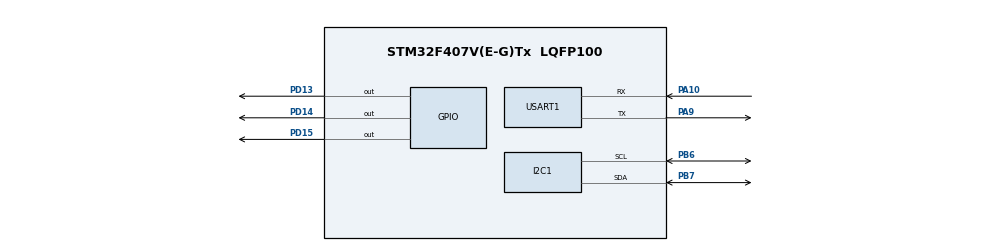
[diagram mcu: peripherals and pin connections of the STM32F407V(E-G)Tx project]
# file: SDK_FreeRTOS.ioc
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FREERTOS.Queues01=myQueue01,16,uint16_t,0,Dynamic,NULL,NULL
FREERTOS.Tasks01=Task_LED1,0,128,StartTaskLED1,Default,NULL,Dynamic,NULL,NULL;Task_UART,0,128,StartTaskUART,Default,NULL,Dynamic,NULL,NULL;Task_LED2,0,128,StartTasLED2,Default,NULL,Dynamic,NULL,NULL
FREERTOS.configENABLE_BACKWARD_COMPATIBILITY=0
FREERTOS.configGENERATE_RUN_TIME_STATS=1
FREERTOS.configUSE_STATS_FORMATTING_FUNCTIONS=1
FREERTOS.configUSE_TRACE_FACILITY=1
Mcu.Family=STM32F4
Mcu.Name=STM32F407V(E-G)Tx
Mcu.Package=LQFP100
NVIC.PriorityGroup=NVIC_PRIORITYGROUP_4
NVIC.TIM1_UP_TIM10_IRQn=true\:0\:0\:false\:false\:true\:false\:false\:true\:true
NVIC.TimeBase=TIM1_UP_TIM10_IRQn
NVIC.TimeBaseIP=TIM1
PA10.Mode=Asynchronous
PA10.Signal=USART1_RX
PA13.Mode=JTAG_5_pins
PA13.Signal=SYS_JTMS-SWDIO
PA14.Mode=JTAG_5_pins
PA14.Signal=SYS_JTCK-SWCLK
PA15.Mode=JTAG_5_pins
PA15.Signal=SYS_JTDI
PA9.Mode=Asynchronous
PA9.Signal=USART1_TX
PB3.Mode=JTAG_5_pins
PB3.Signal=SYS_JTDO-SWO
PB4.Mode=JTAG_5_pins
PB4.Signal=SYS_JTRST
PB6.Mode=I2C
PB6.Signal=I2C1_SCL
PB7.Mode=I2C
PB7.Signal=I2C1_SDA
PD13.Signal=GPIO_Output
PD14.Signal=GPIO_Output
PD15.Signal=GPIO_Output
PH0-OSC_IN.Mode=HSE-External-Oscillator
PH0-OSC_IN.Signal=RCC_OSC_IN
PH1-OSC_OUT.Mode=HSE-External-Oscillator
PH1-OSC_OUT.Signal=RCC_OSC_OUT
ProjectManager.HeapSize=0x200
ProjectManager.StackSize=0x400
ProjectManager.TargetToolchain=STM32CubeIDE
RCC.AHBFreq_Value=16000000
RCC.APB1Freq_Value=16000000
RCC.APB2Freq_Value=16000000
RCC.CortexFreq_Value=16000000
RCC.HSE_VALUE=25000000
RCC.HSI_VALUE=16000000
RCC.LSE_VALUE=32768
RCC.SYSCLKFreq_VALUE=16000000
RCC.VCOOutputFreq_Value=192000000
USART1.VirtualMode=VM_ASYNC
VP_FREERTOS_VS_CMSIS_V1.Mode=CMSIS_V1
VP_SYS_VS_tim1.Mode=TIM1
board=custom

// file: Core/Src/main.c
/**
  ******************************************************************************
  * @file           : main.c
  * @brief          : Main program body
  ******************************************************************************
  * This notice applies to any and all portions of this file
  * that are not between comment pairs USER CODE BEGIN and
  * USER CODE END. Other portions of this file, whether
  * inserted by the user or by software development tools
  * are owned by their respective copyright owners.
  *
  * Copyright (c) 2019 STMicroelectronics International N.V.
  * All rights reserved.
  *
  * Redistribution and use in source and binary forms, with or without
  * modification, are permitted, provided that the following conditions are met:
  *
  * 1. Redistribution of source code must retain the above copyright notice,
  *    this list of conditions and the following disclaimer.
  * 2. Redistributions in binary form must reproduce the above copyright notice,
  *    this list of conditions and the following disclaimer in the documentation
  *    and/or other materials provided with the distribution.
  * 3. Neither the name of STMicroelectronics nor the names of other
  *    contributors to this software may be used to endorse or promote products
  *    derived from this software without specific written permission.
  * 4. This software, including modifications and/or derivative works of this
  *    software, must execute solely and exclusively on microcontroller or
  *    microprocessor devices manufactured by or for STMicroelectronics.
  * 5. Redistribution and use of this software other than as permitted under
  *    this license is void and will automatically terminate your rights under
  *    this license.
  *
  * THIS SOFTWARE IS PROVIDED BY STMICROELECTRONICS AND CONTRIBUTORS "AS IS"
  * AND ANY EXPRESS, IMPLIED OR STATUTORY WARRANTIES, INCLUDING, BUT NOT
  * LIMITED TO, THE IMPLIED WARRANTIES OF MERCHANTABILITY, FITNESS FOR A
  * PARTICULAR PURPOSE AND NON-INFRINGEMENT OF THIRD PARTY INTELLECTUAL PROPERTY
  * RIGHTS ARE DISCLAIMED TO THE FULLEST EXTENT PERMITTED BY LAW. IN NO EVENT
  * SHALL STMICROELECTRONICS OR CONTRIBUTORS BE LIABLE FOR ANY DIRECT, INDIRECT,
  * INCIDENTAL, SPECIAL, EXEMPLARY, OR CONSEQUENTIAL DAMAGES (INCLUDING, BUT NOT
  * LIMITED TO, PROCUREMENT OF SUBSTITUTE GOODS OR SERVICES; LOSS OF USE, DATA,
  * OR PROFITS; OR BUSINESS INTERRUPTION) HOWEVER CAUSED AND ON ANY THEORY OF
  * LIABILITY, WHETHER IN CONTRACT, STRICT LIABILITY, OR TORT (INCLUDING
  * NEGLIGENCE OR OTHERWISE) ARISING IN ANY WAY OUT OF THE USE OF THIS SOFTWARE,
  * EVEN IF ADVISED OF THE POSSIBILITY OF SUCH DAMAGE.
  *
  ******************************************************************************
  */
/* USER CODE END Header */

#include "main.h"
#include "cmsis_os.h"
#include "usart.h"
#include "gpio.h"
#include "oled.h"

void SystemClock_Config(void);
void MX_FREERTOS_Init(void);
/* USER CODE BEGIN PFP */
void MX_I2C1_Init(void);
/* USER CODE END PFP */

int main(void)
{

  /* MCU Configuration--------------------------------------------------------*/

  /* Reset of all peripherals, Initializes the Flash interface and the Systick. */
  HAL_Init();

  /* Configure the system clock */
  SystemClock_Config();

  /* Initialize all configured peripherals */
  MX_GPIO_Init();
  MX_USART1_UART_Init();
  /* USER CODE BEGIN 2 */
  MX_I2C1_Init();
  oled_Init();
  /* USER CODE END 2 */

  /* Call init function for freertos objects (in freertos.c) */
  MX_FREERTOS_Init();
  /* Start scheduler */
  osKernelStart();

  /* We should never get here as control is now taken by the scheduler */
  /* Infinite loop */
  while (1)
  {

  }
}

void SystemClock_Config(void)
{
  RCC_OscInitTypeDef RCC_OscInitStruct = {0};
  RCC_ClkInitTypeDef RCC_ClkInitStruct = {0};

  __HAL_RCC_PWR_CLK_ENABLE();
  __HAL_PWR_VOLTAGESCALING_CONFIG(PWR_REGULATOR_VOLTAGE_SCALE1);

  RCC_OscInitStruct.OscillatorType = RCC_OSCILLATORTYPE_HSE;
  RCC_OscInitStruct.HSEState = RCC_HSE_ON;
  RCC_OscInitStruct.PLL.PLLState = RCC_PLL_ON;
  RCC_OscInitStruct.PLL.PLLSource = RCC_PLLSOURCE_HSE;
  RCC_OscInitStruct.PLL.PLLM = 25;
  RCC_OscInitStruct.PLL.PLLN = 336;
  RCC_OscInitStruct.PLL.PLLP = RCC_PLLP_DIV2;
  RCC_OscInitStruct.PLL.PLLQ = 4;
  if (HAL_RCC_OscConfig(&RCC_OscInitStruct) != HAL_OK)
  {
    Error_Handler();
  }

  RCC_ClkInitStruct.ClockType = RCC_CLOCKTYPE_HCLK|RCC_CLOCKTYPE_SYSCLK
                              |RCC_CLOCKTYPE_PCLK1|RCC_CLOCKTYPE_PCLK2;
  RCC_ClkInitStruct.SYSCLKSource = RCC_SYSCLKSOURCE_PLLCLK;
  RCC_ClkInitStruct.AHBCLKDivider = RCC_SYSCLK_DIV1;
  RCC_ClkInitStruct.APB1CLKDivider = RCC_HCLK_DIV4;
  RCC_ClkInitStruct.APB2CLKDivider = RCC_HCLK_DIV2;

  if (HAL_RCC_ClockConfig(&RCC_ClkInitStruct, FLASH_LATENCY_5) != HAL_OK)
  {
    Error_Handler();
  }
}

 /**
  * @brief  Period elapsed callback in non blocking mode
  * @note   This function is called  when TIM1 interrupt took place, inside
  * HAL_TIM_IRQHandler(). It makes a direct call to HAL_IncTick() to increment
  * a global variable "uwTick" used as application time base.
  * @param  htim : TIM handle
  * @retval None
  */
void HAL_TIM_PeriodElapsedCallback(TIM_HandleTypeDef *htim)
{
  if (htim->Instance == TIM1) {
    HAL_IncTick();
  }
}

void Error_Handler(void)
{
}

/************************ (C) COPYRIGHT STMicroelectronics *****END OF FILE****/

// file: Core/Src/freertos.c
/* USER CODE BEGIN Header */
/**
  ******************************************************************************
  * File Name          : freertos.c
  * Description        : Code for freertos applications
  ******************************************************************************
  * This notice applies to any and all portions of this file
  * that are not between comment pairs USER CODE BEGIN and
  * USER CODE END. Other portions of this file, whether
  * inserted by the user or by software development tools
  * are owned by their respective copyright owners.
  *
  * Copyright (c) 2019 STMicroelectronics International N.V.
  * All rights reserved.
  *
  * Redistribution and use in source and binary forms, with or without
  * modification, are permitted, provided that the following conditions are met:
  *
  * 1. Redistribution of source code must retain the above copyright notice,
  *    this list of conditions and the following disclaimer.
  * 2. Redistributions in binary form must reproduce the above copyright notice,
  *    this list of conditions and the following disclaimer in the documentation
  *    and/or other materials provided with the distribution.
  * 3. Neither the name of STMicroelectronics nor the names of other
  *    contributors to this software may be used to endorse or promote products
  *    derived from this software without specific written permission.
  * 4. This software, including modifications and/or derivative works of this
  *    software, must execute solely and exclusively on microcontroller or
  *    microprocessor devices manufactured by or for STMicroelectronics.
  * 5. Redistribution and use of this software other than as permitted under
  *    this license is void and will automatically terminate your rights under
  *    this license.
  *
  * THIS SOFTWARE IS PROVIDED BY STMICROELECTRONICS AND CONTRIBUTORS "AS IS"
  * AND ANY EXPRESS, IMPLIED OR STATUTORY WARRANTIES, INCLUDING, BUT NOT
  * LIMITED TO, THE IMPLIED WARRANTIES OF MERCHANTABILITY, FITNESS FOR A
  * PARTICULAR PURPOSE AND NON-INFRINGEMENT OF THIRD PARTY INTELLECTUAL PROPERTY
  * RIGHTS ARE DISCLAIMED TO THE FULLEST EXTENT PERMITTED BY LAW. IN NO EVENT
  * SHALL STMICROELECTRONICS OR CONTRIBUTORS BE LIABLE FOR ANY DIRECT, INDIRECT,
  * INCIDENTAL, SPECIAL, EXEMPLARY, OR CONSEQUENTIAL DAMAGES (INCLUDING, BUT NOT
  * LIMITED TO, PROCUREMENT OF SUBSTITUTE GOODS OR SERVICES; LOSS OF USE, DATA,
  * OR PROFITS; OR BUSINESS INTERRUPTION) HOWEVER CAUSED AND ON ANY THEORY OF
  * LIABILITY, WHETHER IN CONTRACT, STRICT LIABILITY, OR TORT (INCLUDING
  * NEGLIGENCE OR OTHERWISE) ARISING IN ANY WAY OUT OF THE USE OF THIS SOFTWARE,
  * EVEN IF ADVISED OF THE POSSIBILITY OF SUCH DAMAGE.
  *
  ******************************************************************************
  */
/* USER CODE END Header */

#include "FreeRTOS.h"
#include "task.h"
#include "main.h"
#include "cmsis_os.h"

/* USER CODE BEGIN Includes */
#include "usart.h"
#include "pca9538.h"
#include <string.h>
/* USER CODE END Includes */

/* USER CODE BEGIN PD */
#define KBRD_ADDR 0xE2
/* USER CODE END PD */

/* USER CODE BEGIN Variables */
osMessageQId xInputQueueHandle;
/* USER CODE END Variables */
osThreadId Task_LED1Handle;
osThreadId Task_UARTHandle;
osThreadId Task_LED2Handle;
osMessageQId myQueue01Handle;

/* USER CODE BEGIN FunctionPrototypes */
void StartTaskInput(void const * argument);
void StartTaskGame(void const * argument);
/* USER CODE END FunctionPrototypes */

void MX_FREERTOS_Init(void); /* (MISRA C 2004 rule 8.1) */

/* GetIdleTaskMemory prototype (linked to static allocation support) */
void vApplicationGetIdleTaskMemory( StaticTask_t **ppxIdleTaskTCBBuffer, StackType_t **ppxIdleTaskStackBuffer, uint32_t *pulIdleTaskStackSize );

/* Hook prototypes */
void configureTimerForRunTimeStats(void);
unsigned long getRunTimeCounterValue(void);

/* USER CODE BEGIN 1 */
/* Functions needed when configGENERATE_RUN_TIME_STATS is on */
__weak void configureTimerForRunTimeStats(void)
{

}

__weak unsigned long getRunTimeCounterValue(void)
{
return 0;
}
/* USER CODE END 1 */

/* USER CODE BEGIN GET_IDLE_TASK_MEMORY */
static StaticTask_t xIdleTaskTCBBuffer;
static StackType_t xIdleStack[configMINIMAL_STACK_SIZE];

void vApplicationGetIdleTaskMemory( StaticTask_t **ppxIdleTaskTCBBuffer, StackType_t **ppxIdleTaskStackBuffer, uint32_t *pulIdleTaskStackSize )
{
  *ppxIdleTaskTCBBuffer = &xIdleTaskTCBBuffer;
  *ppxIdleTaskStackBuffer = &xIdleStack[0];
  *pulIdleTaskStackSize = configMINIMAL_STACK_SIZE;
  /* place for user code */
}
/* USER CODE END GET_IDLE_TASK_MEMORY */

void MX_FREERTOS_Init(void) {

  /* Create the queue(s) */
  /* definition and creation of myQueue01 */
  osMessageQDef(myQueue01, 16, uint16_t);
  myQueue01Handle = osMessageCreate(osMessageQ(myQueue01), NULL);

  /* USER CODE BEGIN RTOS_THREADS */
  osMessageQDef(InputQueue, 10, uint8_t);
  xInputQueueHandle = osMessageCreate(osMessageQ(InputQueue), NULL);
  /* USER CODE END RTOS_QUEUES */

  /* Create the thread(s) */
  /* definition and creation of Task_LED1 */

  /* USER CODE BEGIN RTOS_THREADS */
  vQueueAddToRegistry(myQueue01Handle, "queue1");
  osThreadDef(InputTask, StartTaskInput, osPriorityNormal, 0, 256); // 256 words стека
  osThreadCreate(osThread(InputTask), NULL);

  osThreadDef(GameTask, StartTaskGame, osPriorityAboveNormal, 0, 512);
  osThreadCreate(osThread(GameTask), NULL);
  /* USER CODE END RTOS_THREADS */

}

void StartTaskLED1(void const * argument)
{
  /* USER CODE BEGIN StartTaskLED1 */
  /* Infinite loop */
  uint32_t state;
  for(;;)
  {
	  HAL_GPIO_TogglePin(GPIOD, GPIO_PIN_15);
	  if (HAL_GPIO_ReadPin(GPIOD,GPIO_PIN_15) == GPIO_PIN_SET) {
		  state = 0x01;
		  osMessagePut(myQueue01Handle, state, 100);
	  } else {
		  state = 0x00;
		  osMessagePut(myQueue01Handle, state, 100);
	  }
	  osDelay(500);
  }
  /* USER CODE END StartTaskLED1 */
}

void StartTaskUART(void const * argument)
{
  /* USER CODE BEGIN StartTaskUART */
  /* Infinite loop */
	osEvent event;
	char *state;
	for(;;)
	  {
		event = osMessageGet(myQueue01Handle, 100);
		if (event.status == osEventMessage) {
			state = event.value.v == 0x00 ? "reset\n\r" : "set\n\r";
			HAL_UART_Transmit(&huart1, (uint8_t *)state, strlen(state), 100);
		}
		osDelay(1);
	  }
  /* USER CODE END StartTaskUART */
}

void StartTasLED2(void const * argument)
{
  /* USER CODE BEGIN StartTasLED2 */
  /* Infinite loop */
  for(;;)
  {
	  HAL_GPIO_TogglePin(GPIOD, GPIO_PIN_13);
	  osDelay(400);
  }
  /* USER CODE END StartTasLED2 */
}

/* USER CODE BEGIN Application */
#include "pca9538.h"
#include "tetris.h"

void StartTaskInput(void const * arg) {
    uint8_t cfg, in, prev_key = 0;
    uint8_t buf = 0;

    PCA9538_Write_Register(KBRD_ADDR, POLARITY_INVERSION, &buf);
    PCA9538_Write_Register(KBRD_ADDR, OUTPUT_PORT, &buf);

    for(;;) {
        uint8_t key = 0;
        for (int r = 0; r < 4; r++) {
            cfg = ~(1 << r);
            PCA9538_Write_Register(KBRD_ADDR, CONFIG, &cfg);
            PCA9538_Read_Inputs(KBRD_ADDR, &in);
            in = (~in) & 0x70;
            if (in & 0x10) { key = (r << 4) | 0x01; break; }
            if (in & 0x20) { key = (r << 4) | 0x02; break; }
            if (in & 0x40) { key = (r << 4) | 0x04; break; }
        }
        if (key != 0 && (key != prev_key || key == 0x11)) {
            osMessagePut(xInputQueueHandle, key, 10);
        }
        prev_key = key;
        osDelay(30);
    }
}

void StartTaskGame(void const * arg) {
    TetrisState state;
    Tetris_Init(&state);
    Tetris_Render(&state);

    for(;;) {
        uint32_t timeout = (state.speed < 50) ? 50 : state.speed;

        osEvent ev = osMessageGet(xInputQueueHandle, timeout);

        if (ev.status == osEventMessage) {
            switch(ev.value.v) {
                case 0x01: Tetris_Move(&state, -1, 0); break; // Left
                case 0x02: Tetris_Rotate(&state); break;      // Rotate
                case 0x04: Tetris_Move(&state, 1, 0); break;  // Right
                case 0x11: Tetris_Move(&state, 0, 1); break;  // Soft Drop
                case 0x12:
                    Tetris_Drop(&state);
                    if(Tetris_Step(&state)) {
                        Tetris_Init(&state);
                        Tetris_Render(&state);
                    }
                    break;
                default: break;
            }
        } else {
            if (Tetris_Step(&state)) {
                Tetris_Init(&state);
                Tetris_Render(&state);
            }
        }
        Tetris_Render(&state);
    }
}
/* USER CODE END Application */

/************************ (C) COPYRIGHT STMicroelectronics *****END OF FILE****/
